VERSION 5.7 ;
BUSBITCHARS "[]" ;
DIVIDERCHAR "/" ;

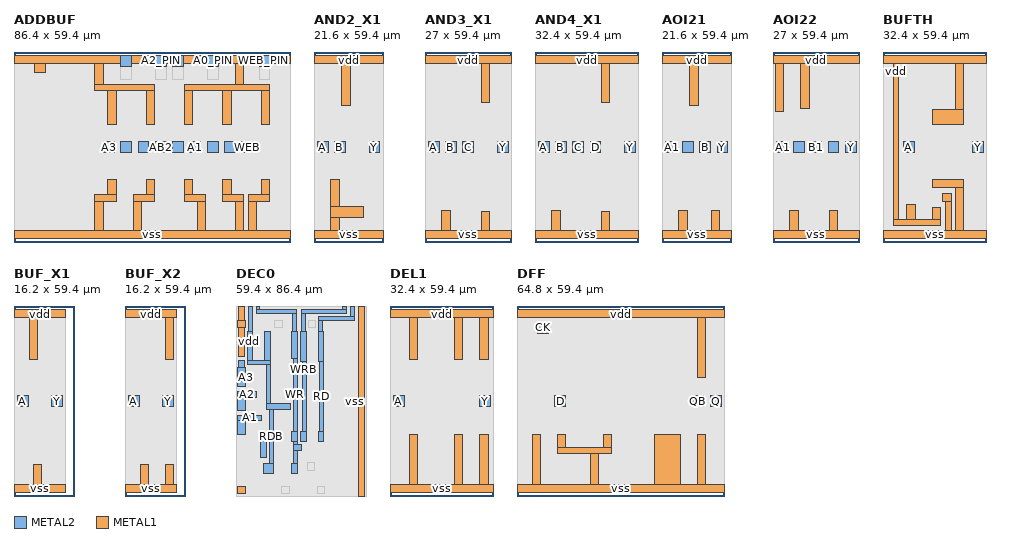
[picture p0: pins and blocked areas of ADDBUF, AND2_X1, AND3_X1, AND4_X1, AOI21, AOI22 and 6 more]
MACRO ADDBUF
  CLASS BLOCK ;
  FOREIGN ADDBUF 48.600 -0.000 ;
  ORIGIN 0.000 0.000 ;
  SIZE 86.400 BY 59.400 ;
  SYMMETRY X Y ;
  PIN A0
    DIRECTION INOUT ;
    USE SIGNAL ;
    PORT
      LAYER METAL2 ;
        RECT 65.800 28.000 69.200 31.400 ;
    END
  END A0
  PIN A0_PIN
    DIRECTION INOUT ;
    USE SIGNAL ;
    PORT
      LAYER METAL2 ;
        RECT 60.400 54.900 63.800 58.300 ;
    END
  END A0_PIN
  PIN A1
    DIRECTION INOUT ;
    USE SIGNAL ;
    PORT
      LAYER METAL2 ;
        RECT 55.000 28.000 58.400 31.400 ;
    END
  END A1
  PIN A1_PIN
    DIRECTION INOUT ;
    USE SIGNAL ;
    PORT
      LAYER METAL2 ;
        RECT 49.600 54.900 53.000 58.300 ;
    END
  END A1_PIN
  PIN A2
    DIRECTION INOUT ;
    USE SIGNAL ;
    PORT
      LAYER METAL2 ;
        RECT 38.800 28.000 42.200 31.400 ;
    END
  END A2
  PIN A2_PIN
    DIRECTION INOUT ;
    USE SIGNAL ;
    PORT
      LAYER METAL2 ;
        RECT 44.200 54.900 47.600 58.300 ;
    END
  END A2_PIN
  PIN A3
    DIRECTION INOUT ;
    USE SIGNAL ;
    PORT
      LAYER METAL2 ;
        RECT 28.000 28.000 31.400 31.400 ;
    END
  END A3
  PIN A3_PIN
    DIRECTION INOUT ;
    USE SIGNAL ;
    PORT
      LAYER METAL2 ;
        RECT 33.400 54.900 36.800 58.300 ;
    END
  END A3_PIN
  PIN AB0
    DIRECTION INOUT ;
    USE SIGNAL ;
    PORT
      LAYER METAL2 ;
        RECT 60.400 28.000 63.800 31.400 ;
    END
  END AB0
  PIN AB1
    DIRECTION INOUT ;
    USE SIGNAL ;
    PORT
      LAYER METAL2 ;
        RECT 49.600 28.000 53.000 31.400 ;
    END
  END AB1
  PIN AB2
    DIRECTION INOUT ;
    USE SIGNAL ;
    PORT
      LAYER METAL2 ;
        RECT 44.200 28.000 47.600 31.400 ;
    END
  END AB2
  PIN AB3
    DIRECTION INOUT ;
    USE SIGNAL ;
    PORT
      LAYER METAL2 ;
        RECT 33.400 28.000 36.800 31.400 ;
    END
  END AB3
  PIN WEB
    DIRECTION INOUT ;
    USE SIGNAL ;
    PORT
      LAYER METAL2 ;
        RECT 71.200 28.000 74.600 31.400 ;
    END
  END WEB
  PIN WEB_PIN
    DIRECTION INOUT ;
    USE SIGNAL ;
    PORT
      LAYER METAL2 ;
        RECT 76.600 54.900 80.000 58.300 ;
    END
  END WEB_PIN
  PIN vdd
    DIRECTION INOUT ;
    USE POWER ;
    PORT
      LAYER METAL1 ;
        RECT 29.300 36.600 31.900 47.400 ;
        RECT 41.300 36.600 43.900 47.400 ;
        RECT 53.300 36.600 55.900 47.400 ;
        RECT 65.300 36.600 67.900 47.400 ;
        RECT 77.300 36.600 79.900 47.400 ;
        RECT 25.300 47.400 43.900 49.200 ;
        RECT 53.300 47.400 79.900 49.200 ;
        RECT 25.300 49.200 27.900 55.700 ;
        RECT 69.300 49.200 71.900 55.700 ;
        RECT 6.400 53.100 9.800 55.700 ;
        RECT 0.000 55.700 86.400 58.300 ;
    END
  END vdd
  PIN vss
    DIRECTION INOUT ;
    USE GROUND ;
    PORT
      LAYER METAL1 ;
        RECT 0.000 1.100 86.400 3.700 ;
        RECT 25.300 3.700 27.900 12.800 ;
        RECT 37.300 3.700 39.900 12.800 ;
        RECT 57.300 3.700 59.900 12.800 ;
        RECT 69.300 3.700 71.900 12.800 ;
        RECT 73.300 3.700 75.900 12.800 ;
        RECT 25.300 12.800 31.900 14.800 ;
        RECT 37.300 12.800 43.900 14.800 ;
        RECT 53.300 12.800 59.900 14.800 ;
        RECT 65.300 12.800 71.900 14.800 ;
        RECT 73.300 12.800 79.900 14.800 ;
        RECT 29.300 14.800 31.900 19.600 ;
        RECT 41.300 14.800 43.900 19.600 ;
        RECT 53.300 14.800 55.900 19.600 ;
        RECT 65.300 14.800 67.900 19.600 ;
        RECT 77.300 14.800 79.900 19.600 ;
    END
  END vss
  OBS
    LAYER METAL1 ;
      RECT 0.000 1.100 86.400 58.300 ;
    LAYER METAL2 ;
      RECT 33.400 50.900 36.800 54.900 ;
      RECT 44.200 50.900 47.600 54.900 ;
      RECT 49.600 50.900 53.000 54.900 ;
      RECT 60.400 50.900 63.800 54.900 ;
      RECT 76.600 50.900 80.000 54.900 ;
  END
END ADDBUF

MACRO AND2_X1
  CLASS CORE ;
  FOREIGN AND2_X1 -0.000 -0.000 ;
  ORIGIN 0.000 0.000 ;
  SIZE 21.600 BY 59.400 ;
  SITE TR1UM ;
  SYMMETRY X Y ;
  PIN A
    DIRECTION INPUT ;
    USE SIGNAL ;
    PORT
      LAYER METAL2 ;
        RECT 1.000 28.000 4.400 31.400 ;
    END
  END A
  PIN B
    DIRECTION INPUT ;
    USE SIGNAL ;
    PORT
      LAYER METAL2 ;
        RECT 6.400 28.000 9.800 31.400 ;
    END
  END B
  PIN Y
    DIRECTION OUTPUT ;
    USE SIGNAL ;
    PORT
      LAYER METAL2 ;
        RECT 17.200 28.000 20.600 31.400 ;
    END
  END Y
  PIN vdd
    DIRECTION INOUT ;
    USE POWER ;
    PORT
      LAYER METAL1 ;
        RECT 8.700 42.700 11.300 55.700 ;
        RECT 0.000 55.700 21.600 58.300 ;
    END
  END vdd
  PIN vss
    DIRECTION INOUT ;
    USE GROUND ;
    PORT
      LAYER METAL1 ;
        RECT 0.000 1.100 21.600 3.700 ;
        RECT 5.300 3.700 7.900 7.700 ;
        RECT 5.300 7.700 15.500 11.100 ;
        RECT 5.300 11.100 7.900 19.600 ;
    END
  END vss
  OBS
    LAYER METAL1 ;
      RECT 0.000 1.100 21.600 58.300 ;
  END
END AND2_X1

MACRO AND3_X1
  CLASS CORE ;
  FOREIGN AND3_X1 -0.000 -0.000 ;
  ORIGIN 0.000 0.000 ;
  SIZE 27.000 BY 59.400 ;
  SITE TR1UM ;
  SYMMETRY X Y ;
  PIN A
    DIRECTION INPUT ;
    USE SIGNAL ;
    PORT
      LAYER METAL2 ;
        RECT 1.000 28.000 4.400 31.400 ;
    END
  END A
  PIN B
    DIRECTION INPUT ;
    USE SIGNAL ;
    PORT
      LAYER METAL2 ;
        RECT 6.400 28.000 9.800 31.400 ;
    END
  END B
  PIN C
    DIRECTION INPUT ;
    USE SIGNAL ;
    PORT
      LAYER METAL2 ;
        RECT 11.800 28.000 15.200 31.400 ;
    END
  END C
  PIN Y
    DIRECTION OUTPUT ;
    USE SIGNAL ;
    PORT
      LAYER METAL2 ;
        RECT 22.600 28.000 26.000 31.400 ;
    END
  END Y
  PIN vdd
    DIRECTION INOUT ;
    USE POWER ;
    PORT
      LAYER METAL1 ;
        RECT 17.700 43.500 20.300 55.700 ;
        RECT 0.000 55.700 27.000 58.300 ;
    END
  END vdd
  PIN vss
    DIRECTION INOUT ;
    USE GROUND ;
    PORT
      LAYER METAL1 ;
        RECT 0.000 1.100 27.000 3.700 ;
        RECT 17.700 3.700 20.300 9.500 ;
        RECT 5.300 3.700 7.900 9.900 ;
    END
  END vss
  OBS
    LAYER METAL1 ;
      RECT 0.000 1.100 27.000 58.300 ;
  END
END AND3_X1

MACRO AND4_X1
  CLASS CORE ;
  FOREIGN AND4_X1 -0.000 -0.000 ;
  ORIGIN 0.000 0.000 ;
  SIZE 32.400 BY 59.400 ;
  SITE TR1UM ;
  SYMMETRY X Y ;
  PIN A
    DIRECTION INPUT ;
    USE SIGNAL ;
    PORT
      LAYER METAL2 ;
        RECT 1.000 28.000 4.400 31.400 ;
    END
  END A
  PIN B
    DIRECTION INPUT ;
    USE SIGNAL ;
    PORT
      LAYER METAL2 ;
        RECT 6.400 28.000 9.800 31.400 ;
    END
  END B
  PIN C
    DIRECTION INPUT ;
    USE SIGNAL ;
    PORT
      LAYER METAL2 ;
        RECT 11.800 28.000 15.200 31.400 ;
    END
  END C
  PIN D
    DIRECTION INPUT ;
    USE SIGNAL ;
    PORT
      LAYER METAL2 ;
        RECT 17.200 28.000 20.600 31.400 ;
    END
  END D
  PIN Y
    DIRECTION OUTPUT ;
    USE SIGNAL ;
    PORT
      LAYER METAL2 ;
        RECT 28.000 28.000 31.400 31.400 ;
    END
  END Y
  PIN vdd
    DIRECTION INOUT ;
    USE POWER ;
    PORT
      LAYER METAL1 ;
        RECT 20.800 43.500 23.400 55.700 ;
        RECT 0.000 55.700 32.400 58.300 ;
    END
  END vdd
  PIN vss
    DIRECTION INOUT ;
    USE GROUND ;
    PORT
      LAYER METAL1 ;
        RECT 0.000 1.100 32.400 3.700 ;
        RECT 20.800 3.700 23.400 9.500 ;
        RECT 5.300 3.700 7.900 9.900 ;
    END
  END vss
  OBS
    LAYER METAL1 ;
      RECT 0.000 1.100 32.400 58.300 ;
  END
END AND4_X1

MACRO AOI21
  CLASS CORE ;
  FOREIGN AOI21 -0.000 -0.000 ;
  ORIGIN 0.000 0.000 ;
  SIZE 21.600 BY 59.400 ;
  SITE TR1UM ;
  SYMMETRY X Y ;
  PIN A1
    DIRECTION INPUT ;
    USE SIGNAL ;
    PORT
      LAYER METAL2 ;
        RECT 1.000 28.000 4.400 31.400 ;
    END
  END A1
  PIN A2
    DIRECTION INPUT ;
    USE SIGNAL ;
    PORT
      LAYER METAL2 ;
        RECT 6.400 28.000 9.800 31.400 ;
    END
  END A2
  PIN B
    DIRECTION INPUT ;
    USE SIGNAL ;
    PORT
      LAYER METAL2 ;
        RECT 11.800 28.000 15.200 31.400 ;
    END
  END B
  PIN Y
    DIRECTION OUTPUT ;
    USE SIGNAL ;
    PORT
      LAYER METAL2 ;
        RECT 17.200 28.000 20.600 31.400 ;
    END
  END Y
  PIN vdd
    DIRECTION INOUT ;
    USE POWER ;
    PORT
      LAYER METAL1 ;
        RECT 8.700 42.700 11.300 55.700 ;
        RECT 0.000 55.700 21.600 58.300 ;
    END
  END vdd
  PIN vss
    DIRECTION INOUT ;
    USE GROUND ;
    PORT
      LAYER METAL1 ;
        RECT 0.000 1.100 21.600 3.700 ;
        RECT 5.300 3.700 7.900 9.900 ;
        RECT 15.500 3.700 18.100 9.900 ;
    END
  END vss
  OBS
    LAYER METAL1 ;
      RECT 0.000 1.100 21.600 58.300 ;
  END
END AOI21

MACRO AOI22
  CLASS CORE ;
  FOREIGN AOI22 -0.000 -0.000 ;
  ORIGIN 0.000 0.000 ;
  SIZE 27.000 BY 59.400 ;
  SITE TR1UM ;
  SYMMETRY X Y ;
  PIN A1
    DIRECTION INPUT ;
    USE SIGNAL ;
    PORT
      LAYER METAL2 ;
        RECT 1.000 28.000 4.400 31.400 ;
    END
  END A1
  PIN A2
    DIRECTION INPUT ;
    USE SIGNAL ;
    PORT
      LAYER METAL2 ;
        RECT 6.400 28.000 9.800 31.400 ;
    END
  END A2
  PIN B1
    DIRECTION INPUT ;
    USE SIGNAL ;
    PORT
      LAYER METAL2 ;
        RECT 11.800 28.000 15.200 31.400 ;
    END
  END B1
  PIN B2
    DIRECTION INPUT ;
    USE SIGNAL ;
    PORT
      LAYER METAL2 ;
        RECT 17.200 28.000 20.600 31.400 ;
    END
  END B2
  PIN Y
    DIRECTION OUTPUT ;
    USE SIGNAL ;
    PORT
      LAYER METAL2 ;
        RECT 22.600 28.000 26.000 31.400 ;
    END
  END Y
  PIN vdd
    DIRECTION INOUT ;
    USE POWER ;
    PORT
      LAYER METAL1 ;
        RECT 0.700 40.900 3.300 55.700 ;
        RECT 8.700 41.700 11.300 55.700 ;
        RECT 0.000 55.700 27.000 58.300 ;
    END
  END vdd
  PIN vss
    DIRECTION INOUT ;
    USE GROUND ;
    PORT
      LAYER METAL1 ;
        RECT 0.000 1.100 27.000 3.700 ;
        RECT 5.300 3.700 7.900 9.900 ;
        RECT 17.700 3.700 20.300 9.900 ;
    END
  END vss
  OBS
    LAYER METAL1 ;
      RECT 0.000 1.100 27.000 58.300 ;
  END
END AOI22

MACRO BUFTH
  CLASS CORE ;
  FOREIGN BUFTH -0.000 -0.000 ;
  ORIGIN 0.000 0.000 ;
  SIZE 32.400 BY 59.400 ;
  SITE TR1UM ;
  SYMMETRY X Y ;
  PIN A
    DIRECTION INPUT ;
    USE SIGNAL ;
    PORT
      LAYER METAL2 ;
        RECT 6.400 28.000 9.800 31.400 ;
    END
  END A
  PIN Y
    DIRECTION OUTPUT ;
    USE SIGNAL ;
    PORT
      LAYER METAL2 ;
        RECT 28.000 28.000 31.400 31.400 ;
    END
  END Y
  PIN vdd
    DIRECTION INOUT ;
    USE POWER ;
    PORT
      LAYER METAL1 ;
        RECT 3.200 5.100 18.100 6.900 ;
        RECT 15.500 6.900 18.100 10.900 ;
        RECT 7.500 6.900 10.100 11.700 ;
        RECT 15.500 36.600 25.300 41.300 ;
        RECT 3.200 6.900 5.000 55.700 ;
        RECT 22.700 41.300 25.300 55.700 ;
        RECT 0.000 55.700 32.400 58.300 ;
    END
  END vdd
  PIN vss
    DIRECTION INOUT ;
    USE GROUND ;
    PORT
      LAYER METAL1 ;
        RECT 0.000 1.100 32.400 3.700 ;
        RECT 19.500 3.700 21.300 12.700 ;
        RECT 18.700 12.700 21.300 15.300 ;
        RECT 22.700 3.700 25.300 17.000 ;
        RECT 15.500 17.000 25.300 19.600 ;
    END
  END vss
  OBS
    LAYER METAL1 ;
      RECT 0.000 1.100 32.400 58.300 ;
  END
END BUFTH

MACRO BUF_X1
  CLASS CORE ;
  FOREIGN BUF_X1 -0.000 -0.000 ;
  ORIGIN 0.000 0.000 ;
  SIZE 16.200 BY 59.400 ;
  SITE TR1UM ;
  SYMMETRY X Y ;
  PIN A
    DIRECTION INPUT ;
    USE SIGNAL ;
    PORT
      LAYER METAL2 ;
        RECT 1.000 28.000 4.400 31.400 ;
    END
  END A
  PIN Y
    DIRECTION OUTPUT ;
    USE SIGNAL ;
    PORT
      LAYER METAL2 ;
        RECT 11.800 28.000 15.200 31.400 ;
    END
  END Y
  PIN vdd
    DIRECTION INOUT ;
    USE POWER ;
    PORT
      LAYER METAL1 ;
        RECT 4.700 42.700 7.300 55.700 ;
        RECT 0.000 55.700 16.200 58.300 ;
    END
  END vdd
  PIN vss
    DIRECTION INOUT ;
    USE GROUND ;
    PORT
      LAYER METAL1 ;
        RECT 0.000 1.100 16.200 3.700 ;
        RECT 6.100 3.700 8.700 9.900 ;
    END
  END vss
  OBS
    LAYER METAL1 ;
      RECT 0.000 1.100 16.200 58.300 ;
  END
END BUF_X1

MACRO BUF_X2
  CLASS CORE ;
  FOREIGN BUF_X2 -0.000 -0.000 ;
  ORIGIN 0.000 0.000 ;
  SIZE 16.200 BY 59.400 ;
  SITE TR1UM ;
  SYMMETRY X Y ;
  PIN A
    DIRECTION INPUT ;
    USE SIGNAL ;
    PORT
      LAYER METAL2 ;
        RECT 1.000 28.000 4.400 31.400 ;
    END
  END A
  PIN Y
    DIRECTION OUTPUT ;
    USE SIGNAL ;
    PORT
      LAYER METAL2 ;
        RECT 11.800 28.000 15.200 31.400 ;
    END
  END Y
  PIN vdd
    DIRECTION INOUT ;
    USE POWER ;
    PORT
      LAYER METAL1 ;
        RECT 12.700 42.700 15.300 55.700 ;
        RECT 0.000 55.700 16.200 58.300 ;
    END
  END vdd
  PIN vss
    DIRECTION INOUT ;
    USE GROUND ;
    PORT
      LAYER METAL1 ;
        RECT 0.000 1.100 16.200 3.700 ;
        RECT 4.700 3.700 7.300 9.900 ;
        RECT 12.700 3.700 15.300 9.900 ;
    END
  END vss
  OBS
    LAYER METAL1 ;
      RECT 0.000 1.100 16.200 58.300 ;
  END
END BUF_X2

MACRO DEC0
  CLASS BLOCK ;
  FOREIGN DEC0 2.400 -0.000 ;
  ORIGIN 0.000 0.000 ;
  SIZE 59.400 BY 86.400 ;
  SYMMETRY X Y ;
  PIN A1
    DIRECTION INOUT ;
    USE SIGNAL ;
    PORT
      LAYER METAL2 ;
        RECT 11.200 17.600 13.800 25.600 ;
        RECT 0.700 28.000 4.100 34.200 ;
        RECT 0.700 34.200 11.600 36.800 ;
    END
  END A1
  PIN A2
    DIRECTION INOUT ;
    USE SIGNAL ;
    PORT
      LAYER METAL2 ;
        RECT 0.700 38.800 4.100 45.000 ;
        RECT 0.700 45.000 9.400 47.600 ;
    END
  END A2
  PIN A3
    DIRECTION INOUT ;
    USE SIGNAL ;
    PORT
      LAYER METAL2 ;
        RECT 0.700 49.600 4.100 58.400 ;
        RECT 1.100 58.400 3.700 61.400 ;
    END
  END A3
  PIN RD
    DIRECTION INOUT ;
    USE SIGNAL ;
    PORT
      LAYER METAL2 ;
        RECT 37.300 24.600 39.900 29.200 ;
        RECT 38.100 29.200 39.900 61.000 ;
        RECT 37.300 61.000 39.900 74.900 ;
        RECT 37.700 74.900 39.500 79.700 ;
        RECT 37.700 79.700 53.900 81.500 ;
        RECT 52.100 81.500 53.900 86.400 ;
    END
  END RD
  PIN RDB
    DIRECTION INOUT ;
    USE SIGNAL ;
    PORT
      LAYER METAL2 ;
        RECT 12.700 10.100 17.000 14.700 ;
        RECT 15.200 14.700 17.000 39.400 ;
        RECT 13.900 39.400 24.700 42.000 ;
        RECT 13.900 42.000 15.700 59.800 ;
        RECT 5.100 59.800 15.700 61.600 ;
        RECT 5.100 61.600 7.700 74.900 ;
        RECT 13.100 61.600 15.700 74.900 ;
        RECT 5.500 74.900 7.300 86.400 ;
    END
  END RDB
  PIN WR
    DIRECTION INOUT ;
    USE SIGNAL ;
    PORT
      LAYER METAL2 ;
        RECT 25.300 10.100 27.900 14.700 ;
        RECT 26.100 14.700 27.900 20.600 ;
        RECT 26.100 20.600 29.700 23.200 ;
        RECT 26.100 23.200 27.900 24.600 ;
        RECT 25.300 24.600 27.900 29.200 ;
        RECT 26.100 29.200 27.900 62.700 ;
        RECT 25.300 62.700 27.900 74.900 ;
        RECT 25.700 74.900 27.500 82.900 ;
        RECT 9.100 82.900 27.500 84.700 ;
        RECT 9.100 84.700 10.900 86.400 ;
    END
  END WR
  PIN WRB
    DIRECTION INOUT ;
    USE SIGNAL ;
    PORT
      LAYER METAL2 ;
        RECT 29.300 24.600 31.900 29.200 ;
        RECT 30.100 29.200 31.900 61.000 ;
        RECT 29.300 61.000 31.900 74.900 ;
        RECT 29.700 74.900 31.500 82.900 ;
        RECT 29.700 82.900 50.300 84.700 ;
        RECT 48.500 84.700 50.300 86.400 ;
    END
  END WRB
  PIN vdd
    DIRECTION INOUT ;
    USE POWER ;
    PORT
      LAYER METAL1 ;
        RECT 0.700 76.600 4.100 80.000 ;
        RECT 1.100 63.500 3.700 76.600 ;
        RECT 0.700 76.600 4.100 80.000 ;
        RECT 1.100 80.000 3.700 86.400 ;
    END
  END vdd
  PIN vss
    DIRECTION INOUT ;
    USE GROUND ;
    PORT
      LAYER METAL1 ;
        RECT 0.700 1.000 4.100 4.400 ;
        RECT 55.700 0.000 58.300 86.400 ;
    END
  END vss
  OBS
    LAYER METAL1 ;
      RECT 0.000 0.000 59.400 86.400 ;
    LAYER METAL2 ;
      RECT 20.900 1.000 24.300 4.400 ;
      RECT 36.900 1.000 40.300 4.400 ;
      RECT 32.500 11.800 35.900 15.200 ;
      RECT 17.700 76.600 21.100 80.000 ;
      RECT 32.900 76.600 36.300 80.000 ;
  END
END DEC0

MACRO DEC16
  CLASS BLOCK ;
  FOREIGN DEC16 57.000 0.000 ;
  ORIGIN 0.000 0.000 ;
  SIZE 878.400 BY 86.400 ;
  SYMMETRY X Y ;
  # ★ ピン未定義: GDS のトップにラベル/(49,1) 形状を入れて再生成すること

  OBS
    LAYER METAL1 ;
      RECT 0.000 0.000 878.400 86.400 ;
    LAYER METAL2 ;
      RECT 0.000 0.000 878.400 86.400 ;
  END
END DEC16

MACRO DEC2
  CLASS BLOCK ;
  FOREIGN DEC2 57.000 0.000 ;
  ORIGIN 0.000 0.000 ;
  SIZE 114.000 BY 86.400 ;
  SYMMETRY X Y ;
  # ★ ピン未定義: GDS のトップにラベル/(49,1) 形状を入れて再生成すること

  OBS
    LAYER METAL1 ;
      RECT 0.000 0.000 114.000 86.400 ;
    LAYER METAL2 ;
      RECT 0.000 0.000 114.000 86.400 ;
  END
END DEC2

MACRO DEL1
  CLASS CORE ;
  FOREIGN DEL1 -0.000 -0.000 ;
  ORIGIN 0.000 0.000 ;
  SIZE 32.400 BY 59.400 ;
  SITE TR1UM ;
  SYMMETRY X Y ;
  PIN A
    DIRECTION INPUT ;
    USE SIGNAL ;
    PORT
      LAYER METAL2 ;
        RECT 1.000 28.000 4.400 31.400 ;
    END
  END A
  PIN Y
    DIRECTION OUTPUT ;
    USE SIGNAL ;
    PORT
      LAYER METAL2 ;
        RECT 28.000 28.000 31.400 31.400 ;
    END
  END Y
  PIN vdd
    DIRECTION INOUT ;
    USE POWER ;
    PORT
      LAYER METAL1 ;
        RECT 6.100 42.700 8.700 55.700 ;
        RECT 20.100 42.700 22.700 55.700 ;
        RECT 28.100 42.700 30.700 55.700 ;
        RECT 0.000 55.700 32.400 58.300 ;
    END
  END vdd
  PIN vss
    DIRECTION INOUT ;
    USE GROUND ;
    PORT
      LAYER METAL1 ;
        RECT 0.000 1.100 32.400 3.700 ;
        RECT 6.100 3.700 8.700 19.100 ;
        RECT 20.100 3.700 22.700 19.100 ;
        RECT 28.100 3.700 30.700 19.100 ;
    END
  END vss
  OBS
    LAYER METAL1 ;
      RECT 0.000 1.100 32.400 58.300 ;
  END
END DEL1

MACRO DFF
  CLASS CORE ;
  FOREIGN DFF -0.000 -0.000 ;
  ORIGIN 0.000 0.000 ;
  SIZE 64.800 BY 59.400 ;
  SITE TR1UM ;
  SYMMETRY X Y ;
  PIN CK
    DIRECTION INPUT ;
    USE SIGNAL ;
    PORT
      LAYER METAL2 ;
        RECT 6.400 50.900 9.800 54.300 ;
    END
  END CK
  PIN D
    DIRECTION INPUT ;
    USE SIGNAL ;
    PORT
      LAYER METAL2 ;
        RECT 11.800 27.900 15.200 31.300 ;
    END
  END D
  PIN Q
    DIRECTION OUTPUT ;
    USE SIGNAL ;
    PORT
      LAYER METAL2 ;
        RECT 60.400 27.900 63.800 31.300 ;
    END
  END Q
  PIN QB
    DIRECTION OUTPUT ;
    USE SIGNAL ;
    PORT
      LAYER METAL2 ;
        RECT 55.000 27.900 58.400 31.300 ;
    END
  END QB
  PIN vdd
    DIRECTION INOUT ;
    USE POWER ;
    PORT
      LAYER METAL1 ;
        RECT 56.400 36.900 59.000 55.700 ;
        RECT 0.000 55.700 64.800 58.300 ;
    END
  END vdd
  PIN vss
    DIRECTION INOUT ;
    USE GROUND ;
    PORT
      LAYER METAL1 ;
        RECT 0.000 1.100 64.800 3.700 ;
        RECT 22.900 3.700 25.500 13.400 ;
        RECT 12.700 13.400 29.500 15.200 ;
        RECT 4.700 3.700 7.300 19.200 ;
        RECT 42.900 3.700 51.000 19.200 ;
        RECT 56.400 3.700 59.000 19.200 ;
        RECT 12.700 15.200 15.300 19.200 ;
        RECT 26.900 15.200 29.500 19.200 ;
    END
  END vss
  OBS
    LAYER METAL1 ;
      RECT 0.000 1.100 64.800 58.300 ;
  END
END DFF

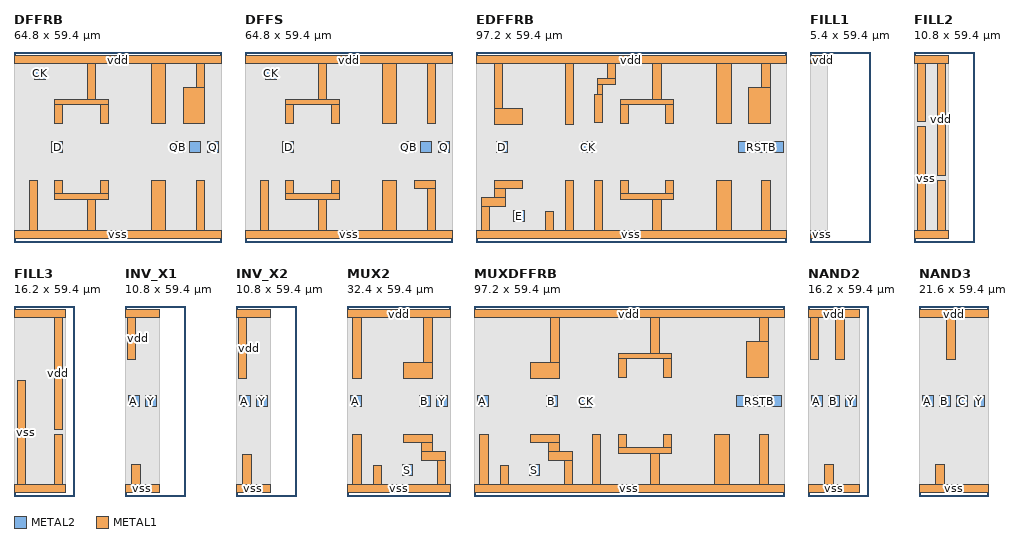
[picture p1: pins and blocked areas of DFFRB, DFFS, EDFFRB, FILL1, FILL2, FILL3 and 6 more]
MACRO DFFRB
  CLASS CORE ;
  FOREIGN DFFRB -0.000 -0.000 ;
  ORIGIN 0.000 0.000 ;
  SIZE 64.800 BY 59.400 ;
  SITE TR1UM ;
  SYMMETRY X Y ;
  PIN CK
    DIRECTION INPUT ;
    USE SIGNAL ;
    PORT
      LAYER METAL2 ;
        RECT 6.400 50.900 9.800 54.300 ;
    END
  END CK
  PIN D
    DIRECTION INPUT ;
    USE SIGNAL ;
    PORT
      LAYER METAL2 ;
        RECT 11.800 27.900 15.200 31.300 ;
    END
  END D
  PIN Q
    DIRECTION OUTPUT ;
    USE SIGNAL ;
    PORT
      LAYER METAL2 ;
        RECT 60.400 27.900 63.800 31.300 ;
    END
  END Q
  PIN QB
    DIRECTION OUTPUT ;
    USE SIGNAL ;
    PORT
      LAYER METAL2 ;
        RECT 49.600 27.900 53.000 31.300 ;
    END
  END QB
  PIN RSTB
    DIRECTION INPUT ;
    USE SIGNAL ;
    PORT
      LAYER METAL2 ;
        RECT 55.000 27.900 58.400 31.300 ;
    END
  END RSTB
  PIN vdd
    DIRECTION INOUT ;
    USE POWER ;
    PORT
      LAYER METAL1 ;
        RECT 12.700 36.900 15.300 42.900 ;
        RECT 26.900 36.900 29.500 42.900 ;
        RECT 12.700 42.900 29.500 44.700 ;
        RECT 52.900 36.900 59.600 48.400 ;
        RECT 42.900 36.900 47.500 55.700 ;
        RECT 22.900 44.700 25.500 55.700 ;
        RECT 57.000 48.400 59.600 55.700 ;
        RECT 0.000 55.700 64.800 58.300 ;
    END
  END vdd
  PIN vss
    DIRECTION INOUT ;
    USE GROUND ;
    PORT
      LAYER METAL1 ;
        RECT 0.000 1.100 64.800 3.700 ;
        RECT 22.900 3.700 25.500 13.400 ;
        RECT 12.700 13.400 29.500 15.200 ;
        RECT 4.700 3.700 7.300 19.200 ;
        RECT 42.900 3.700 47.500 19.200 ;
        RECT 57.000 3.700 59.600 19.200 ;
        RECT 12.700 15.200 15.300 19.200 ;
        RECT 26.900 15.200 29.500 19.200 ;
    END
  END vss
  OBS
    LAYER METAL1 ;
      RECT 0.000 1.100 64.800 58.300 ;
  END
END DFFRB

MACRO DFFS
  CLASS CORE ;
  FOREIGN DFFS -0.000 -0.000 ;
  ORIGIN 0.000 0.000 ;
  SIZE 64.800 BY 59.400 ;
  SITE TR1UM ;
  SYMMETRY X Y ;
  PIN CK
    DIRECTION INPUT ;
    USE SIGNAL ;
    PORT
      LAYER METAL2 ;
        RECT 6.400 50.900 9.800 54.300 ;
    END
  END CK
  PIN D
    DIRECTION INPUT ;
    USE SIGNAL ;
    PORT
      LAYER METAL2 ;
        RECT 11.800 27.900 15.200 31.300 ;
    END
  END D
  PIN Q
    DIRECTION OUTPUT ;
    USE SIGNAL ;
    PORT
      LAYER METAL2 ;
        RECT 60.400 27.900 63.800 31.300 ;
    END
  END Q
  PIN QB
    DIRECTION OUTPUT ;
    USE SIGNAL ;
    PORT
      LAYER METAL2 ;
        RECT 49.600 27.900 53.000 31.300 ;
    END
  END QB
  PIN SET
    DIRECTION INPUT ;
    USE SIGNAL ;
    PORT
      LAYER METAL2 ;
        RECT 55.000 27.900 58.400 31.300 ;
    END
  END SET
  PIN vdd
    DIRECTION INOUT ;
    USE POWER ;
    PORT
      LAYER METAL1 ;
        RECT 12.700 36.900 15.300 42.900 ;
        RECT 26.900 36.900 29.500 42.900 ;
        RECT 12.700 42.900 29.500 44.700 ;
        RECT 42.900 36.900 47.500 55.700 ;
        RECT 57.000 36.900 59.600 55.700 ;
        RECT 22.900 44.700 25.500 55.700 ;
        RECT 0.000 55.700 64.800 58.300 ;
    END
  END vdd
  PIN vss
    DIRECTION INOUT ;
    USE GROUND ;
    PORT
      LAYER METAL1 ;
        RECT 0.000 1.100 64.800 3.700 ;
        RECT 22.900 3.700 25.500 13.400 ;
        RECT 12.700 13.400 29.500 15.200 ;
        RECT 57.000 3.700 59.600 16.600 ;
        RECT 4.700 3.700 7.300 19.200 ;
        RECT 42.900 3.700 47.500 19.200 ;
        RECT 12.700 15.200 15.300 19.200 ;
        RECT 26.900 15.200 29.500 19.200 ;
        RECT 52.900 16.600 59.600 19.200 ;
    END
  END vss
  OBS
    LAYER METAL1 ;
      RECT 0.000 1.100 64.800 58.300 ;
  END
END DFFS

MACRO EDFFRB
  CLASS CORE ;
  FOREIGN EDFFRB -0.000 -0.000 ;
  ORIGIN 0.000 0.000 ;
  SIZE 97.200 BY 59.400 ;
  SITE TR1UM ;
  SYMMETRY X Y ;
  PIN CK
    DIRECTION INPUT ;
    USE SIGNAL ;
    PORT
      LAYER METAL2 ;
        RECT 33.400 27.900 36.800 31.300 ;
    END
  END CK
  PIN D
    DIRECTION INPUT ;
    USE SIGNAL ;
    PORT
      LAYER METAL2 ;
        RECT 6.400 27.900 9.800 31.300 ;
    END
  END D
  PIN E
    DIRECTION INPUT ;
    USE SIGNAL ;
    PORT
      LAYER METAL2 ;
        RECT 11.800 6.300 15.200 9.700 ;
    END
  END E
  PIN Q
    DIRECTION OUTPUT ;
    USE SIGNAL ;
    PORT
      LAYER METAL2 ;
        RECT 92.800 27.900 96.200 31.300 ;
    END
  END Q
  PIN QB
    DIRECTION OUTPUT ;
    USE SIGNAL ;
    PORT
      LAYER METAL2 ;
        RECT 82.000 27.900 85.400 31.300 ;
    END
  END QB
  PIN RSTB
    DIRECTION INPUT ;
    USE SIGNAL ;
    PORT
      LAYER METAL2 ;
        RECT 87.400 27.900 90.800 31.300 ;
    END
  END RSTB
  PIN vdd
    DIRECTION INOUT ;
    USE POWER ;
    PORT
      LAYER METAL1 ;
        RECT 5.800 36.700 14.600 41.700 ;
        RECT 45.100 36.900 47.700 42.900 ;
        RECT 59.300 36.900 61.900 42.900 ;
        RECT 45.100 42.900 61.900 44.700 ;
        RECT 37.100 37.500 39.700 46.100 ;
        RECT 85.300 36.900 92.000 48.400 ;
        RECT 37.900 46.100 39.700 49.300 ;
        RECT 37.900 49.300 43.700 51.100 ;
        RECT 28.000 36.700 30.600 55.700 ;
        RECT 75.300 36.900 79.900 55.700 ;
        RECT 5.800 41.700 8.400 55.700 ;
        RECT 55.300 44.700 57.900 55.700 ;
        RECT 89.400 48.400 92.000 55.700 ;
        RECT 41.100 51.100 43.700 55.700 ;
        RECT 0.000 55.700 97.200 58.300 ;
    END
  END vdd
  PIN vss
    DIRECTION INOUT ;
    USE GROUND ;
    PORT
      LAYER METAL1 ;
        RECT 0.000 1.100 97.200 3.700 ;
        RECT 21.600 3.700 24.200 9.500 ;
        RECT 1.600 3.700 4.200 11.200 ;
        RECT 55.300 3.700 57.900 13.400 ;
        RECT 1.600 11.200 9.100 13.800 ;
        RECT 45.100 13.400 61.900 15.200 ;
        RECT 5.800 13.800 9.100 16.600 ;
        RECT 37.100 3.700 39.700 19.200 ;
        RECT 75.300 3.700 79.900 19.200 ;
        RECT 89.400 3.700 92.000 19.200 ;
        RECT 45.100 15.200 47.700 19.200 ;
        RECT 59.300 15.200 61.900 19.200 ;
        RECT 28.000 3.700 30.600 19.300 ;
        RECT 5.800 16.600 14.600 19.300 ;
    END
  END vss
  OBS
    LAYER METAL1 ;
      RECT 0.000 1.100 97.200 58.300 ;
  END
END EDFFRB

MACRO FILL1
  CLASS CORE SPACER ;
  FOREIGN FILL1 -0.000 -0.000 ;
  ORIGIN 0.000 0.000 ;
  SIZE 5.400 BY 59.400 ;
  SITE TR1UM ;
  SYMMETRY X Y ;
  PIN vdd
    DIRECTION INOUT ;
    USE POWER ;
    PORT
      LAYER METAL1 ;
        RECT 0.000 55.700 5.400 58.300 ;
    END
  END vdd
  PIN vss
    DIRECTION INOUT ;
    USE GROUND ;
    PORT
      LAYER METAL1 ;
        RECT 0.000 1.100 5.400 3.700 ;
    END
  END vss
  OBS
    LAYER METAL1 ;
      RECT 0.000 1.100 5.400 58.300 ;
  END
END FILL1

MACRO FILL2
  CLASS CORE SPACER ;
  FOREIGN FILL2 -0.000 -0.000 ;
  ORIGIN 0.000 0.000 ;
  SIZE 10.800 BY 59.400 ;
  SITE TR1UM ;
  SYMMETRY X Y ;
  PIN vdd
    DIRECTION INOUT ;
    USE POWER ;
    PORT
      LAYER METAL1 ;
        RECT 7.200 20.700 9.800 55.700 ;
        RECT 1.000 37.700 3.600 55.700 ;
        RECT 0.000 55.700 10.800 58.300 ;
    END
  END vdd
  PIN vss
    DIRECTION INOUT ;
    USE GROUND ;
    PORT
      LAYER METAL1 ;
        RECT 0.000 1.100 10.800 3.700 ;
        RECT 7.200 3.700 9.800 19.100 ;
        RECT 1.000 3.700 3.600 36.100 ;
    END
  END vss
  OBS
    LAYER METAL1 ;
      RECT 0.000 1.100 10.800 58.300 ;
  END
END FILL2

MACRO FILL3
  CLASS CORE SPACER ;
  FOREIGN FILL3 -0.000 -0.000 ;
  ORIGIN 0.000 0.000 ;
  SIZE 16.200 BY 59.400 ;
  SITE TR1UM ;
  SYMMETRY X Y ;
  PIN vdd
    DIRECTION INOUT ;
    USE POWER ;
    PORT
      LAYER METAL1 ;
        RECT 12.600 20.700 15.200 55.700 ;
        RECT 0.000 55.700 16.200 58.300 ;
    END
  END vdd
  PIN vss
    DIRECTION INOUT ;
    USE GROUND ;
    PORT
      LAYER METAL1 ;
        RECT 0.000 1.100 16.200 3.700 ;
        RECT 12.600 3.700 15.200 19.100 ;
        RECT 1.000 3.700 3.600 36.100 ;
    END
  END vss
  OBS
    LAYER METAL1 ;
      RECT 0.000 1.100 16.200 58.300 ;
  END
END FILL3

MACRO INV_X1
  CLASS CORE ;
  FOREIGN INV_X1 -0.000 -0.000 ;
  ORIGIN 0.000 0.000 ;
  SIZE 10.800 BY 59.400 ;
  SITE TR1UM ;
  SYMMETRY X Y ;
  PIN A
    DIRECTION INPUT ;
    USE SIGNAL ;
    PORT
      LAYER METAL2 ;
        RECT 1.000 28.000 4.400 31.400 ;
    END
  END A
  PIN Y
    DIRECTION OUTPUT ;
    USE SIGNAL ;
    PORT
      LAYER METAL2 ;
        RECT 6.400 28.000 9.800 31.400 ;
    END
  END Y
  PIN vdd
    DIRECTION INOUT ;
    USE POWER ;
    PORT
      LAYER METAL1 ;
        RECT 0.700 42.700 3.300 55.700 ;
        RECT 0.000 55.700 10.800 58.300 ;
    END
  END vdd
  PIN vss
    DIRECTION INOUT ;
    USE GROUND ;
    PORT
      LAYER METAL1 ;
        RECT 0.000 1.100 10.800 3.700 ;
        RECT 2.100 3.700 4.700 9.900 ;
    END
  END vss
  OBS
    LAYER METAL1 ;
      RECT 0.000 1.100 10.800 58.300 ;
  END
END INV_X1

MACRO INV_X2
  CLASS CORE ;
  FOREIGN INV_X2 -0.000 -0.000 ;
  ORIGIN 0.000 0.000 ;
  SIZE 10.800 BY 59.400 ;
  SITE TR1UM ;
  SYMMETRY X Y ;
  PIN A
    DIRECTION INPUT ;
    USE SIGNAL ;
    PORT
      LAYER METAL2 ;
        RECT 1.000 28.000 4.400 31.400 ;
    END
  END A
  PIN Y
    DIRECTION OUTPUT ;
    USE SIGNAL ;
    PORT
      LAYER METAL2 ;
        RECT 6.400 28.000 9.800 31.400 ;
    END
  END Y
  PIN vdd
    DIRECTION INOUT ;
    USE POWER ;
    PORT
      LAYER METAL1 ;
        RECT 0.700 36.700 3.300 55.700 ;
        RECT 0.000 55.700 10.800 58.300 ;
    END
  END vdd
  PIN vss
    DIRECTION INOUT ;
    USE GROUND ;
    PORT
      LAYER METAL1 ;
        RECT 0.000 1.100 10.800 3.700 ;
        RECT 2.100 3.700 4.700 13.100 ;
    END
  END vss
  OBS
    LAYER METAL1 ;
      RECT 0.000 1.100 10.800 58.300 ;
  END
END INV_X2

MACRO MUX2
  CLASS CORE ;
  FOREIGN MUX2 -0.000 -0.000 ;
  ORIGIN 0.000 0.000 ;
  SIZE 32.400 BY 59.400 ;
  SITE TR1UM ;
  SYMMETRY X Y ;
  PIN A
    DIRECTION INPUT ;
    USE SIGNAL ;
    PORT
      LAYER METAL2 ;
        RECT 1.000 27.900 4.400 31.300 ;
    END
  END A
  PIN B
    DIRECTION INPUT ;
    USE SIGNAL ;
    PORT
      LAYER METAL2 ;
        RECT 22.600 27.900 26.000 31.300 ;
    END
  END B
  PIN S
    DIRECTION INPUT ;
    USE SIGNAL ;
    PORT
      LAYER METAL2 ;
        RECT 17.200 6.300 20.600 9.700 ;
    END
  END S
  PIN Y
    DIRECTION OUTPUT ;
    USE SIGNAL ;
    PORT
      LAYER METAL2 ;
        RECT 28.000 27.900 31.400 31.300 ;
    END
  END Y
  PIN vdd
    DIRECTION INOUT ;
    USE POWER ;
    PORT
      LAYER METAL1 ;
        RECT 17.800 36.700 26.600 41.700 ;
        RECT 1.800 36.700 4.400 55.700 ;
        RECT 24.000 41.700 26.600 55.700 ;
        RECT 0.000 55.700 32.400 58.300 ;
    END
  END vdd
  PIN vss
    DIRECTION INOUT ;
    USE GROUND ;
    PORT
      LAYER METAL1 ;
        RECT 0.000 1.100 32.400 3.700 ;
        RECT 8.200 3.700 10.800 9.500 ;
        RECT 28.200 3.700 30.800 11.200 ;
        RECT 23.300 11.200 30.800 13.800 ;
        RECT 23.300 13.800 26.600 16.600 ;
        RECT 1.800 3.700 4.400 19.300 ;
        RECT 17.800 16.600 26.600 19.300 ;
    END
  END vss
  OBS
    LAYER METAL1 ;
      RECT 0.000 1.100 32.400 58.300 ;
  END
END MUX2

MACRO MUXDFFRB
  CLASS CORE ;
  FOREIGN MUXDFFRB -0.000 -0.000 ;
  ORIGIN 0.000 0.000 ;
  SIZE 97.200 BY 59.400 ;
  SITE TR1UM ;
  SYMMETRY X Y ;
  PIN A
    DIRECTION INPUT ;
    USE SIGNAL ;
    PORT
      LAYER METAL2 ;
        RECT 1.000 27.900 4.400 31.300 ;
    END
  END A
  PIN B
    DIRECTION INPUT ;
    USE SIGNAL ;
    PORT
      LAYER METAL2 ;
        RECT 22.600 27.900 26.000 31.300 ;
    END
  END B
  PIN CK
    DIRECTION INPUT ;
    USE SIGNAL ;
    PORT
      LAYER METAL2 ;
        RECT 33.400 27.700 36.800 31.100 ;
    END
  END CK
  PIN Q
    DIRECTION OUTPUT ;
    USE SIGNAL ;
    PORT
      LAYER METAL2 ;
        RECT 92.800 27.900 96.200 31.300 ;
    END
  END Q
  PIN QB
    DIRECTION OUTPUT ;
    USE SIGNAL ;
    PORT
      LAYER METAL2 ;
        RECT 82.000 27.900 85.400 31.300 ;
    END
  END QB
  PIN RSTB
    DIRECTION INPUT ;
    USE SIGNAL ;
    PORT
      LAYER METAL2 ;
        RECT 87.400 27.900 90.800 31.300 ;
    END
  END RSTB
  PIN S
    DIRECTION INPUT ;
    USE SIGNAL ;
    PORT
      LAYER METAL2 ;
        RECT 17.200 6.300 20.600 9.700 ;
    END
  END S
  PIN vdd
    DIRECTION INOUT ;
    USE POWER ;
    PORT
      LAYER METAL1 ;
        RECT 17.800 36.700 26.600 41.700 ;
        RECT 45.100 36.900 47.700 42.900 ;
        RECT 59.300 36.900 61.900 42.900 ;
        RECT 45.100 42.900 61.900 44.700 ;
        RECT 85.300 36.900 92.000 48.400 ;
        RECT 24.000 41.700 26.600 55.700 ;
        RECT 55.300 44.700 57.900 55.700 ;
        RECT 89.400 48.400 92.000 55.700 ;
        RECT 0.000 55.700 97.200 58.300 ;
    END
  END vdd
  PIN vss
    DIRECTION INOUT ;
    USE GROUND ;
    PORT
      LAYER METAL1 ;
        RECT 0.000 1.100 97.200 3.700 ;
        RECT 8.200 3.700 10.800 9.500 ;
        RECT 28.200 3.700 30.800 11.200 ;
        RECT 55.300 3.700 57.900 13.400 ;
        RECT 23.300 11.200 30.800 13.800 ;
        RECT 45.100 13.400 61.900 15.200 ;
        RECT 23.300 13.800 26.600 16.600 ;
        RECT 37.100 3.700 39.700 19.200 ;
        RECT 75.300 3.700 79.900 19.200 ;
        RECT 89.400 3.700 92.000 19.200 ;
        RECT 45.100 15.200 47.700 19.200 ;
        RECT 59.300 15.200 61.900 19.200 ;
        RECT 1.800 3.700 4.400 19.300 ;
        RECT 17.800 16.600 26.600 19.300 ;
    END
  END vss
  OBS
    LAYER METAL1 ;
      RECT 0.000 1.100 97.200 58.300 ;
  END
END MUXDFFRB

MACRO NAND2
  CLASS CORE ;
  FOREIGN NAND2 -0.000 -0.000 ;
  ORIGIN 0.000 0.000 ;
  SIZE 16.200 BY 59.400 ;
  SITE TR1UM ;
  SYMMETRY X Y ;
  PIN A
    DIRECTION INPUT ;
    USE SIGNAL ;
    PORT
      LAYER METAL2 ;
        RECT 1.000 28.000 4.400 31.400 ;
    END
  END A
  PIN B
    DIRECTION INPUT ;
    USE SIGNAL ;
    PORT
      LAYER METAL2 ;
        RECT 6.400 28.000 9.800 31.400 ;
    END
  END B
  PIN Y
    DIRECTION OUTPUT ;
    USE SIGNAL ;
    PORT
      LAYER METAL2 ;
        RECT 11.800 28.000 15.200 31.400 ;
    END
  END Y
  PIN vdd
    DIRECTION INOUT ;
    USE POWER ;
    PORT
      LAYER METAL1 ;
        RECT 0.700 42.700 3.300 55.700 ;
        RECT 8.700 42.700 11.300 55.700 ;
        RECT 0.000 55.700 16.200 58.300 ;
    END
  END vdd
  PIN vss
    DIRECTION INOUT ;
    USE GROUND ;
    PORT
      LAYER METAL1 ;
        RECT 0.000 1.100 16.200 3.700 ;
        RECT 5.300 3.700 7.900 9.900 ;
    END
  END vss
  OBS
    LAYER METAL1 ;
      RECT 0.000 1.100 16.200 58.300 ;
  END
END NAND2

MACRO NAND3
  CLASS CORE ;
  FOREIGN NAND3 -0.000 -0.000 ;
  ORIGIN 0.000 0.000 ;
  SIZE 21.600 BY 59.400 ;
  SITE TR1UM ;
  SYMMETRY X Y ;
  PIN A
    DIRECTION INPUT ;
    USE SIGNAL ;
    PORT
      LAYER METAL2 ;
        RECT 1.000 28.000 4.400 31.400 ;
    END
  END A
  PIN B
    DIRECTION INPUT ;
    USE SIGNAL ;
    PORT
      LAYER METAL2 ;
        RECT 6.400 28.000 9.800 31.400 ;
    END
  END B
  PIN C
    DIRECTION INPUT ;
    USE SIGNAL ;
    PORT
      LAYER METAL2 ;
        RECT 11.800 28.000 15.200 31.400 ;
    END
  END C
  PIN Y
    DIRECTION OUTPUT ;
    USE SIGNAL ;
    PORT
      LAYER METAL2 ;
        RECT 17.200 28.000 20.600 31.400 ;
    END
  END Y
  PIN vdd
    DIRECTION INOUT ;
    USE POWER ;
    PORT
      LAYER METAL1 ;
        RECT 8.700 42.700 11.300 55.700 ;
        RECT 0.000 55.700 21.600 58.300 ;
    END
  END vdd
  PIN vss
    DIRECTION INOUT ;
    USE GROUND ;
    PORT
      LAYER METAL1 ;
        RECT 0.000 1.100 21.600 3.700 ;
        RECT 5.300 3.700 7.900 9.900 ;
    END
  END vss
  OBS
    LAYER METAL1 ;
      RECT 0.000 1.100 21.600 58.300 ;
  END
END NAND3

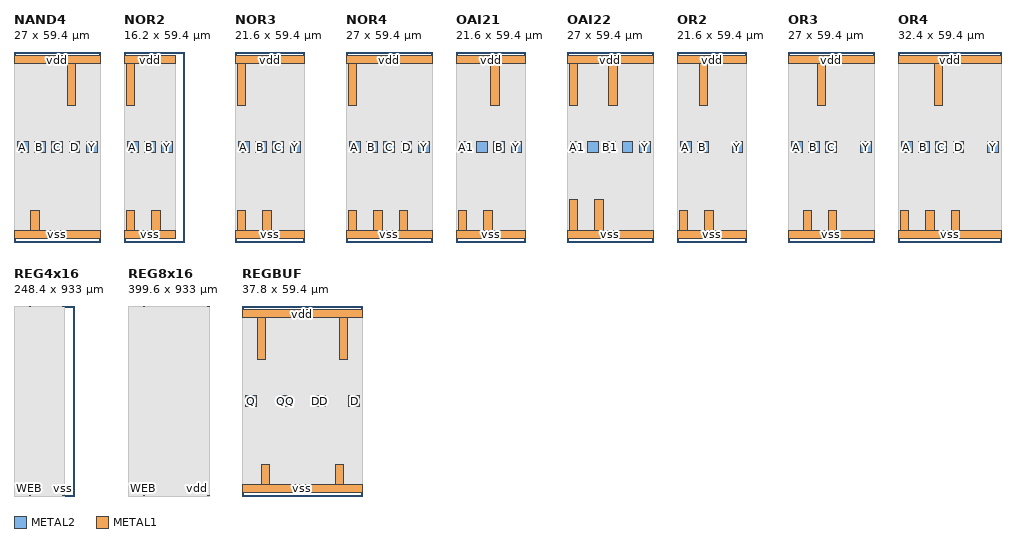
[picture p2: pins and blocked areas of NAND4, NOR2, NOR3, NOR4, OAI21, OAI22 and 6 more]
MACRO NAND4
  CLASS CORE ;
  FOREIGN NAND4 -0.000 -0.000 ;
  ORIGIN 0.000 0.000 ;
  SIZE 27.000 BY 59.400 ;
  SITE TR1UM ;
  SYMMETRY X Y ;
  PIN A
    DIRECTION INPUT ;
    USE SIGNAL ;
    PORT
      LAYER METAL2 ;
        RECT 1.000 28.000 4.400 31.400 ;
    END
  END A
  PIN B
    DIRECTION INPUT ;
    USE SIGNAL ;
    PORT
      LAYER METAL2 ;
        RECT 6.400 28.000 9.800 31.400 ;
    END
  END B
  PIN C
    DIRECTION INPUT ;
    USE SIGNAL ;
    PORT
      LAYER METAL2 ;
        RECT 11.800 28.000 15.200 31.400 ;
    END
  END C
  PIN D
    DIRECTION INPUT ;
    USE SIGNAL ;
    PORT
      LAYER METAL2 ;
        RECT 17.200 28.000 20.600 31.400 ;
    END
  END D
  PIN Y
    DIRECTION OUTPUT ;
    USE SIGNAL ;
    PORT
      LAYER METAL2 ;
        RECT 22.600 28.000 26.000 31.400 ;
    END
  END Y
  PIN vdd
    DIRECTION INOUT ;
    USE POWER ;
    PORT
      LAYER METAL1 ;
        RECT 16.700 42.700 19.300 55.700 ;
        RECT 0.000 55.700 27.000 58.300 ;
    END
  END vdd
  PIN vss
    DIRECTION INOUT ;
    USE GROUND ;
    PORT
      LAYER METAL1 ;
        RECT 0.000 1.100 27.000 3.700 ;
        RECT 5.300 3.700 7.900 9.900 ;
    END
  END vss
  OBS
    LAYER METAL1 ;
      RECT 0.000 1.100 27.000 58.300 ;
  END
END NAND4

MACRO NOR2
  CLASS CORE ;
  FOREIGN NOR2 -0.000 -0.000 ;
  ORIGIN 0.000 0.000 ;
  SIZE 16.200 BY 59.400 ;
  SITE TR1UM ;
  SYMMETRY X Y ;
  PIN A
    DIRECTION INPUT ;
    USE SIGNAL ;
    PORT
      LAYER METAL2 ;
        RECT 1.000 28.000 4.400 31.400 ;
    END
  END A
  PIN B
    DIRECTION INPUT ;
    USE SIGNAL ;
    PORT
      LAYER METAL2 ;
        RECT 6.400 28.000 9.800 31.400 ;
    END
  END B
  PIN Y
    DIRECTION OUTPUT ;
    USE SIGNAL ;
    PORT
      LAYER METAL2 ;
        RECT 11.800 28.000 15.200 31.400 ;
    END
  END Y
  PIN vdd
    DIRECTION INOUT ;
    USE POWER ;
    PORT
      LAYER METAL1 ;
        RECT 0.700 42.700 3.300 55.700 ;
        RECT 0.000 55.700 16.200 58.300 ;
    END
  END vdd
  PIN vss
    DIRECTION INOUT ;
    USE GROUND ;
    PORT
      LAYER METAL1 ;
        RECT 0.000 1.100 16.200 3.700 ;
        RECT 0.700 3.700 3.300 9.900 ;
        RECT 8.700 3.700 11.300 9.900 ;
    END
  END vss
  OBS
    LAYER METAL1 ;
      RECT 0.000 1.100 16.200 58.300 ;
  END
END NOR2

MACRO NOR3
  CLASS CORE ;
  FOREIGN NOR3 -0.000 -0.000 ;
  ORIGIN 0.000 0.000 ;
  SIZE 21.600 BY 59.400 ;
  SITE TR1UM ;
  SYMMETRY X Y ;
  PIN A
    DIRECTION INPUT ;
    USE SIGNAL ;
    PORT
      LAYER METAL2 ;
        RECT 1.000 28.000 4.400 31.400 ;
    END
  END A
  PIN B
    DIRECTION INPUT ;
    USE SIGNAL ;
    PORT
      LAYER METAL2 ;
        RECT 6.400 28.000 9.800 31.400 ;
    END
  END B
  PIN C
    DIRECTION INPUT ;
    USE SIGNAL ;
    PORT
      LAYER METAL2 ;
        RECT 11.800 28.000 15.200 31.400 ;
    END
  END C
  PIN Y
    DIRECTION OUTPUT ;
    USE SIGNAL ;
    PORT
      LAYER METAL2 ;
        RECT 17.200 28.000 20.600 31.400 ;
    END
  END Y
  PIN vdd
    DIRECTION INOUT ;
    USE POWER ;
    PORT
      LAYER METAL1 ;
        RECT 0.700 42.700 3.300 55.700 ;
        RECT 0.000 55.700 21.600 58.300 ;
    END
  END vdd
  PIN vss
    DIRECTION INOUT ;
    USE GROUND ;
    PORT
      LAYER METAL1 ;
        RECT 0.000 1.100 21.600 3.700 ;
        RECT 0.700 3.700 3.300 9.900 ;
        RECT 8.700 3.700 11.300 9.900 ;
    END
  END vss
  OBS
    LAYER METAL1 ;
      RECT 0.000 1.100 21.600 58.300 ;
  END
END NOR3

MACRO NOR4
  CLASS CORE ;
  FOREIGN NOR4 -0.000 -0.000 ;
  ORIGIN 0.000 0.000 ;
  SIZE 27.000 BY 59.400 ;
  SITE TR1UM ;
  SYMMETRY X Y ;
  PIN A
    DIRECTION INPUT ;
    USE SIGNAL ;
    PORT
      LAYER METAL2 ;
        RECT 1.000 28.000 4.400 31.400 ;
    END
  END A
  PIN B
    DIRECTION INPUT ;
    USE SIGNAL ;
    PORT
      LAYER METAL2 ;
        RECT 6.400 28.000 9.800 31.400 ;
    END
  END B
  PIN C
    DIRECTION INPUT ;
    USE SIGNAL ;
    PORT
      LAYER METAL2 ;
        RECT 11.800 28.000 15.200 31.400 ;
    END
  END C
  PIN D
    DIRECTION INPUT ;
    USE SIGNAL ;
    PORT
      LAYER METAL2 ;
        RECT 17.200 28.000 20.600 31.400 ;
    END
  END D
  PIN Y
    DIRECTION OUTPUT ;
    USE SIGNAL ;
    PORT
      LAYER METAL2 ;
        RECT 22.600 28.000 26.000 31.400 ;
    END
  END Y
  PIN vdd
    DIRECTION INOUT ;
    USE POWER ;
    PORT
      LAYER METAL1 ;
        RECT 0.700 42.700 3.300 55.700 ;
        RECT 0.000 55.700 27.000 58.300 ;
    END
  END vdd
  PIN vss
    DIRECTION INOUT ;
    USE GROUND ;
    PORT
      LAYER METAL1 ;
        RECT 0.000 1.100 27.000 3.700 ;
        RECT 0.700 3.700 3.300 9.900 ;
        RECT 8.700 3.700 11.300 9.900 ;
        RECT 16.700 3.700 19.300 9.900 ;
    END
  END vss
  OBS
    LAYER METAL1 ;
      RECT 0.000 1.100 27.000 58.300 ;
  END
END NOR4

MACRO OAI21
  CLASS CORE ;
  FOREIGN OAI21 -0.000 -0.000 ;
  ORIGIN 0.000 0.000 ;
  SIZE 21.600 BY 59.400 ;
  SITE TR1UM ;
  SYMMETRY X Y ;
  PIN A1
    DIRECTION INPUT ;
    USE SIGNAL ;
    PORT
      LAYER METAL2 ;
        RECT 1.000 28.000 4.400 31.400 ;
    END
  END A1
  PIN A2
    DIRECTION INPUT ;
    USE SIGNAL ;
    PORT
      LAYER METAL2 ;
        RECT 6.400 28.000 9.800 31.400 ;
    END
  END A2
  PIN B
    DIRECTION INPUT ;
    USE SIGNAL ;
    PORT
      LAYER METAL2 ;
        RECT 11.800 28.000 15.200 31.400 ;
    END
  END B
  PIN Y
    DIRECTION OUTPUT ;
    USE SIGNAL ;
    PORT
      LAYER METAL2 ;
        RECT 17.200 28.000 20.600 31.400 ;
    END
  END Y
  PIN vdd
    DIRECTION INOUT ;
    USE POWER ;
    PORT
      LAYER METAL1 ;
        RECT 10.900 42.700 13.500 55.700 ;
        RECT 0.000 55.700 21.600 58.300 ;
    END
  END vdd
  PIN vss
    DIRECTION INOUT ;
    USE GROUND ;
    PORT
      LAYER METAL1 ;
        RECT 0.000 1.100 21.600 3.700 ;
        RECT 0.700 3.700 3.300 9.900 ;
        RECT 8.700 3.700 11.300 9.900 ;
    END
  END vss
  OBS
    LAYER METAL1 ;
      RECT 0.000 1.100 21.600 58.300 ;
  END
END OAI21

MACRO OAI22
  CLASS CORE ;
  FOREIGN OAI22 -0.000 -0.000 ;
  ORIGIN 0.000 0.000 ;
  SIZE 27.000 BY 59.400 ;
  SITE TR1UM ;
  SYMMETRY X Y ;
  PIN A1
    DIRECTION INPUT ;
    USE SIGNAL ;
    PORT
      LAYER METAL2 ;
        RECT 1.000 28.000 4.400 31.400 ;
    END
  END A1
  PIN A2
    DIRECTION INPUT ;
    USE SIGNAL ;
    PORT
      LAYER METAL2 ;
        RECT 6.400 28.000 9.800 31.400 ;
    END
  END A2
  PIN B1
    DIRECTION INPUT ;
    USE SIGNAL ;
    PORT
      LAYER METAL2 ;
        RECT 11.800 28.000 15.200 31.400 ;
    END
  END B1
  PIN B2
    DIRECTION INPUT ;
    USE SIGNAL ;
    PORT
      LAYER METAL2 ;
        RECT 17.200 28.000 20.600 31.400 ;
    END
  END B2
  PIN Y
    DIRECTION OUTPUT ;
    USE SIGNAL ;
    PORT
      LAYER METAL2 ;
        RECT 22.600 28.000 26.000 31.400 ;
    END
  END Y
  PIN vdd
    DIRECTION INOUT ;
    USE POWER ;
    PORT
      LAYER METAL1 ;
        RECT 0.700 42.700 3.300 55.700 ;
        RECT 13.100 42.700 15.700 55.700 ;
        RECT 0.000 55.700 27.000 58.300 ;
    END
  END vdd
  PIN vss
    DIRECTION INOUT ;
    USE GROUND ;
    PORT
      LAYER METAL1 ;
        RECT 0.000 1.100 27.000 3.700 ;
        RECT 0.700 3.700 3.300 13.400 ;
        RECT 8.700 3.700 11.300 13.400 ;
    END
  END vss
  OBS
    LAYER METAL1 ;
      RECT 0.000 1.100 27.000 58.300 ;
  END
END OAI22

MACRO OR2
  CLASS CORE ;
  FOREIGN OR2 -0.000 -0.000 ;
  ORIGIN 0.000 0.000 ;
  SIZE 21.600 BY 59.400 ;
  SITE TR1UM ;
  SYMMETRY X Y ;
  PIN A
    DIRECTION INPUT ;
    USE SIGNAL ;
    PORT
      LAYER METAL2 ;
        RECT 1.000 28.000 4.400 31.400 ;
    END
  END A
  PIN B
    DIRECTION INPUT ;
    USE SIGNAL ;
    PORT
      LAYER METAL2 ;
        RECT 6.400 28.000 9.800 31.400 ;
    END
  END B
  PIN Y
    DIRECTION OUTPUT ;
    USE SIGNAL ;
    PORT
      LAYER METAL2 ;
        RECT 17.200 28.000 20.600 31.400 ;
    END
  END Y
  PIN vdd
    DIRECTION INOUT ;
    USE POWER ;
    PORT
      LAYER METAL1 ;
        RECT 6.900 42.700 9.500 55.700 ;
        RECT 0.000 55.700 21.600 58.300 ;
    END
  END vdd
  PIN vss
    DIRECTION INOUT ;
    USE GROUND ;
    PORT
      LAYER METAL1 ;
        RECT 0.000 1.100 21.600 3.700 ;
        RECT 0.700 3.700 3.300 9.900 ;
        RECT 8.700 3.700 11.300 9.900 ;
    END
  END vss
  OBS
    LAYER METAL1 ;
      RECT 0.000 1.100 21.600 58.300 ;
  END
END OR2

MACRO OR3
  CLASS CORE ;
  FOREIGN OR3 -0.000 -0.000 ;
  ORIGIN 0.000 0.000 ;
  SIZE 27.000 BY 59.400 ;
  SITE TR1UM ;
  SYMMETRY X Y ;
  PIN A
    DIRECTION INPUT ;
    USE SIGNAL ;
    PORT
      LAYER METAL2 ;
        RECT 1.000 28.000 4.400 31.400 ;
    END
  END A
  PIN B
    DIRECTION INPUT ;
    USE SIGNAL ;
    PORT
      LAYER METAL2 ;
        RECT 6.400 28.000 9.800 31.400 ;
    END
  END B
  PIN C
    DIRECTION INPUT ;
    USE SIGNAL ;
    PORT
      LAYER METAL2 ;
        RECT 11.800 28.000 15.200 31.400 ;
    END
  END C
  PIN Y
    DIRECTION OUTPUT ;
    USE SIGNAL ;
    PORT
      LAYER METAL2 ;
        RECT 22.600 28.000 26.000 31.400 ;
    END
  END Y
  PIN vdd
    DIRECTION INOUT ;
    USE POWER ;
    PORT
      LAYER METAL1 ;
        RECT 9.100 42.700 11.700 55.700 ;
        RECT 0.000 55.700 27.000 58.300 ;
    END
  END vdd
  PIN vss
    DIRECTION INOUT ;
    USE GROUND ;
    PORT
      LAYER METAL1 ;
        RECT 0.000 1.100 27.000 3.700 ;
        RECT 4.700 3.700 7.300 9.900 ;
        RECT 12.700 3.700 15.300 9.900 ;
    END
  END vss
  OBS
    LAYER METAL1 ;
      RECT 0.000 1.100 27.000 58.300 ;
  END
END OR3

MACRO OR4
  CLASS CORE ;
  FOREIGN OR4 -0.000 -0.000 ;
  ORIGIN 0.000 0.000 ;
  SIZE 32.400 BY 59.400 ;
  SITE TR1UM ;
  SYMMETRY X Y ;
  PIN A
    DIRECTION INPUT ;
    USE SIGNAL ;
    PORT
      LAYER METAL2 ;
        RECT 1.000 28.000 4.400 31.400 ;
    END
  END A
  PIN B
    DIRECTION INPUT ;
    USE SIGNAL ;
    PORT
      LAYER METAL2 ;
        RECT 6.400 28.000 9.800 31.400 ;
    END
  END B
  PIN C
    DIRECTION INPUT ;
    USE SIGNAL ;
    PORT
      LAYER METAL2 ;
        RECT 11.800 28.000 15.200 31.400 ;
    END
  END C
  PIN D
    DIRECTION INPUT ;
    USE SIGNAL ;
    PORT
      LAYER METAL2 ;
        RECT 17.200 28.000 20.600 31.400 ;
    END
  END D
  PIN Y
    DIRECTION OUTPUT ;
    USE SIGNAL ;
    PORT
      LAYER METAL2 ;
        RECT 28.000 28.000 31.400 31.400 ;
    END
  END Y
  PIN vdd
    DIRECTION INOUT ;
    USE POWER ;
    PORT
      LAYER METAL1 ;
        RECT 11.300 42.700 13.900 55.700 ;
        RECT 0.000 55.700 32.400 58.300 ;
    END
  END vdd
  PIN vss
    DIRECTION INOUT ;
    USE GROUND ;
    PORT
      LAYER METAL1 ;
        RECT 0.000 1.100 32.400 3.700 ;
        RECT 0.700 3.700 3.300 9.900 ;
        RECT 8.700 3.700 11.300 9.900 ;
        RECT 16.700 3.700 19.300 9.900 ;
    END
  END vss
  OBS
    LAYER METAL1 ;
      RECT 0.000 1.100 32.400 58.300 ;
  END
END OR4

MACRO REG4x16
  CLASS BLOCK ;
  FOREIGN REG4x16 -0.000 -0.000 ;
  ORIGIN 0.000 0.000 ;
  SIZE 248.400 BY 933.000 ;
  SYMMETRY X Y ;
  PIN WEB
    DIRECTION INOUT ;
    USE SIGNAL ;
    PORT
      LAYER METAL2 ;
        RECT 6.400 1.100 9.800 4.500 ;
    END
  END WEB
  PIN vdd
    DIRECTION INOUT ;
    USE POWER ;
    PORT
      LAYER METAL1 ;
        RECT 76.600 1.100 80.000 4.500 ;
        RECT 244.000 1.100 247.400 4.500 ;
        RECT 76.600 928.500 80.000 931.900 ;
        RECT 244.000 928.500 247.400 931.900 ;
    END
  END vdd
  PIN vss
    DIRECTION INOUT ;
    USE GROUND ;
    PORT
      LAYER METAL1 ;
        RECT 1.000 1.100 4.400 4.500 ;
        RECT 238.600 1.100 242.000 4.500 ;
        RECT 1.000 928.500 4.400 931.900 ;
        RECT 238.600 928.500 242.000 931.900 ;
    END
  END vss
  OBS
    LAYER METAL1 ;
      RECT 0.000 0.000 248.400 933.000 ;
    LAYER METAL2 ;
      RECT 0.000 0.000 248.400 933.000 ;
  END
END REG4x16

MACRO REG8x16
  CLASS BLOCK ;
  FOREIGN REG8x16 -0.000 -0.000 ;
  ORIGIN 0.000 0.000 ;
  SIZE 399.600 BY 933.000 ;
  SYMMETRY X Y ;
  PIN WEB
    DIRECTION INPUT ;
    USE SIGNAL ;
    PORT
      LAYER METAL2 ;
        RECT 6.400 1.100 9.800 4.500 ;
    END
  END WEB
  PIN vdd
    DIRECTION INOUT ;
    USE POWER ;
    PORT
      LAYER METAL1 ;
        RECT 76.600 1.100 80.000 4.500 ;
        RECT 395.200 1.100 398.600 4.500 ;
        RECT 76.600 928.500 80.000 931.900 ;
        RECT 395.200 928.500 398.600 931.900 ;
    END
  END vdd
  PIN vss
    DIRECTION INOUT ;
    USE GROUND ;
    PORT
      LAYER METAL1 ;
        RECT 1.000 1.100 4.400 4.500 ;
        RECT 389.800 1.100 393.200 4.500 ;
        RECT 1.000 928.500 4.400 931.900 ;
        RECT 389.800 928.500 393.200 931.900 ;
    END
  END vss
  OBS
    LAYER METAL1 ;
      RECT 0.000 0.000 399.600 933.000 ;
    LAYER METAL2 ;
      RECT 0.000 0.000 399.600 933.000 ;
  END
END REG8x16

MACRO REGBUF
  CLASS BLOCK ;
  FOREIGN REGBUF -0.000 -0.000 ;
  ORIGIN 0.000 0.000 ;
  SIZE 37.800 BY 59.400 ;
  SYMMETRY X Y ;
  PIN D
    DIRECTION INOUT ;
    USE SIGNAL ;
    PORT
      LAYER METAL2 ;
        RECT 33.400 28.000 36.800 31.400 ;
    END
  END D
  PIN DD
    DIRECTION INOUT ;
    USE SIGNAL ;
    PORT
      LAYER METAL2 ;
        RECT 22.600 28.000 26.000 31.400 ;
    END
  END DD
  PIN Q
    DIRECTION INOUT ;
    USE SIGNAL ;
    PORT
      LAYER METAL2 ;
        RECT 1.000 28.000 4.400 31.400 ;
    END
  END Q
  PIN QQ
    DIRECTION INOUT ;
    USE SIGNAL ;
    PORT
      LAYER METAL2 ;
        RECT 11.800 28.000 15.200 31.400 ;
    END
  END QQ
  PIN vdd
    DIRECTION INOUT ;
    USE POWER ;
    PORT
      LAYER METAL1 ;
        RECT 4.700 42.700 7.300 55.700 ;
        RECT 30.500 42.700 33.100 55.700 ;
        RECT 0.000 55.700 37.800 58.300 ;
    END
  END vdd
  PIN vss
    DIRECTION INOUT ;
    USE GROUND ;
    PORT
      LAYER METAL1 ;
        RECT 0.000 1.100 37.800 3.700 ;
        RECT 6.100 3.700 8.700 9.900 ;
        RECT 29.100 3.700 31.700 9.900 ;
    END
  END vss
  OBS
    LAYER METAL1 ;
      RECT 0.000 1.100 37.800 58.300 ;
  END
END REGBUF

MACRO REGBUF4
  CLASS BLOCK ;
  FOREIGN REGBUF4 10.800 -0.000 ;
  ORIGIN 0.000 0.000 ;
  SIZE 162.000 BY 59.400 ;
  SYMMETRY X Y ;
  # ★ ピン未定義: GDS のトップにラベル/(49,1) 形状を入れて再生成すること

  OBS
    LAYER METAL1 ;
      RECT 0.000 1.100 162.000 58.300 ;
    LAYER METAL2 ;
      RECT 0.000 0.000 162.000 59.400 ;
  END
END REGBUF4

MACRO REGBUF8
  CLASS BLOCK ;
  FOREIGN REGBUF8 10.800 -0.000 ;
  ORIGIN 0.000 0.000 ;
  SIZE 313.200 BY 59.400 ;
  SYMMETRY X Y ;
  # ★ ピン未定義: GDS のトップにラベル/(49,1) 形状を入れて再生成すること

  OBS
    LAYER METAL1 ;
      RECT 0.000 1.100 313.200 58.300 ;
    LAYER METAL2 ;
      RECT 0.000 0.000 313.200 59.400 ;
  END
END REGBUF8

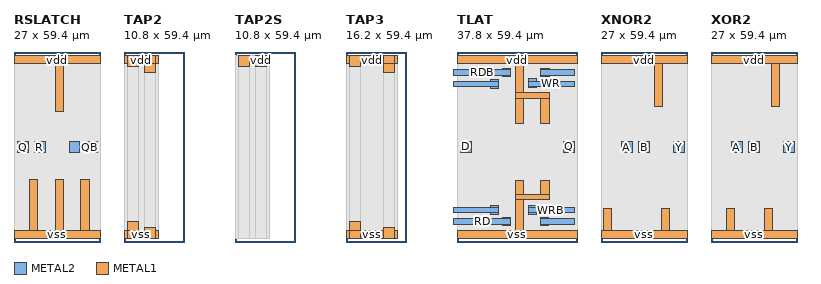
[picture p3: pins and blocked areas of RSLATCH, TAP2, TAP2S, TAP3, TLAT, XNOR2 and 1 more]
MACRO RSLATCH
  CLASS CORE ;
  FOREIGN RSLATCH -0.000 -0.000 ;
  ORIGIN 0.000 0.000 ;
  SIZE 27.000 BY 59.400 ;
  SITE TR1UM ;
  SYMMETRY X Y ;
  PIN Q
    DIRECTION OUTPUT ;
    USE SIGNAL ;
    PORT
      LAYER METAL2 ;
        RECT 1.000 28.000 4.400 31.400 ;
    END
  END Q
  PIN QB
    DIRECTION OUTPUT ;
    USE SIGNAL ;
    PORT
      LAYER METAL2 ;
        RECT 22.600 28.000 26.000 31.400 ;
    END
  END QB
  PIN R
    DIRECTION INPUT ;
    USE SIGNAL ;
    PORT
      LAYER METAL2 ;
        RECT 6.400 28.000 9.800 31.400 ;
    END
  END R
  PIN S
    DIRECTION INPUT ;
    USE SIGNAL ;
    PORT
      LAYER METAL2 ;
        RECT 17.200 28.000 20.600 31.400 ;
    END
  END S
  PIN vdd
    DIRECTION INOUT ;
    USE POWER ;
    PORT
      LAYER METAL1 ;
        RECT 12.900 40.700 15.500 55.700 ;
        RECT 0.000 55.700 27.000 58.300 ;
    END
  END vdd
  PIN vss
    DIRECTION INOUT ;
    USE GROUND ;
    PORT
      LAYER METAL1 ;
        RECT 0.000 1.100 27.000 3.700 ;
        RECT 4.900 3.700 7.500 19.600 ;
        RECT 12.900 3.700 15.500 19.600 ;
        RECT 20.900 3.700 23.500 19.600 ;
    END
  END vss
  OBS
    LAYER METAL1 ;
      RECT 0.000 1.100 27.000 58.300 ;
  END
END RSLATCH

MACRO TAP2
  CLASS CORE WELLTAP ;
  FOREIGN TAP2 -0.000 -0.000 ;
  ORIGIN 0.000 0.000 ;
  SIZE 10.800 BY 59.400 ;
  SITE TR1UM ;
  SYMMETRY X Y ;
  PIN vdd
    DIRECTION INOUT ;
    USE POWER ;
    PORT
      LAYER METAL1 ;
        RECT 6.400 1.100 9.800 4.500 ;
        RECT 6.400 54.900 9.800 58.300 ;
        RECT 6.400 53.100 9.800 55.700 ;
        RECT 0.000 55.700 10.800 58.300 ;
    END
  END vdd
  PIN vss
    DIRECTION INOUT ;
    USE GROUND ;
    PORT
      LAYER METAL1 ;
        RECT 1.000 1.100 4.400 4.500 ;
        RECT 1.000 54.900 4.400 58.300 ;
        RECT 0.000 1.100 10.800 3.700 ;
        RECT 1.000 3.700 4.400 6.300 ;
    END
  END vss
  OBS
    LAYER METAL1 ;
      RECT 0.000 1.100 10.800 58.300 ;
    LAYER METAL2 ;
      RECT 6.400 4.500 9.800 53.100 ;
      RECT 1.000 6.300 4.400 54.900 ;
  END
END TAP2

MACRO TAP2S
  CLASS BLOCK ;
  FOREIGN TAP2S -0.000 -0.000 ;
  ORIGIN 0.000 0.000 ;
  SIZE 10.800 BY 59.400 ;
  SYMMETRY X Y ;
  PIN vdd
    DIRECTION INOUT ;
    USE POWER ;
    PORT
      LAYER METAL1 ;
        RECT 6.400 54.900 9.800 58.300 ;
    END
  END vdd
  PIN vss
    DIRECTION INOUT ;
    USE GROUND ;
    PORT
      LAYER METAL1 ;
        RECT 1.000 54.900 4.400 58.300 ;
    END
  END vss
  OBS
    LAYER METAL1 ;
      RECT 0.000 1.100 10.800 58.300 ;
    LAYER METAL2 ;
      RECT 1.000 1.100 4.400 54.900 ;
      RECT 6.400 1.100 9.800 54.900 ;
  END
END TAP2S

MACRO TAP3
  CLASS CORE WELLTAP ;
  FOREIGN TAP3 -0.000 -0.000 ;
  ORIGIN 0.000 0.000 ;
  SIZE 16.200 BY 59.400 ;
  SITE TR1UM ;
  SYMMETRY X Y ;
  PIN vdd
    DIRECTION INOUT ;
    USE POWER ;
    PORT
      LAYER METAL1 ;
        RECT 11.800 1.100 15.200 4.500 ;
        RECT 11.800 54.900 15.200 58.300 ;
        RECT 11.800 53.100 15.200 55.700 ;
        RECT 0.000 55.700 16.200 58.300 ;
    END
  END vdd
  PIN vss
    DIRECTION INOUT ;
    USE GROUND ;
    PORT
      LAYER METAL1 ;
        RECT 1.000 1.100 4.400 4.500 ;
        RECT 1.000 54.900 4.400 58.300 ;
        RECT 0.000 1.100 16.200 3.700 ;
        RECT 1.000 3.700 4.400 6.300 ;
    END
  END vss
  OBS
    LAYER METAL1 ;
      RECT 0.000 1.100 16.200 58.300 ;
    LAYER METAL2 ;
      RECT 11.800 4.500 15.200 53.100 ;
      RECT 1.000 6.300 4.400 54.900 ;
  END
END TAP3

MACRO TLAT
  CLASS BLOCK ;
  FOREIGN TLAT -0.000 -0.000 ;
  ORIGIN 0.000 0.000 ;
  SIZE 37.800 BY 59.400 ;
  SYMMETRY X Y ;
  PIN D
    DIRECTION INOUT ;
    USE SIGNAL ;
    PORT
      LAYER METAL2 ;
        RECT 1.000 28.100 4.400 31.500 ;
    END
  END D
  PIN Q
    DIRECTION INOUT ;
    USE SIGNAL ;
    PORT
      LAYER METAL2 ;
        RECT 33.400 28.100 36.800 31.500 ;
    END
  END Q
  PIN RD
    DIRECTION INOUT ;
    USE SIGNAL ;
    PORT
      LAYER METAL2 ;
        RECT 14.200 5.100 16.800 5.500 ;
        RECT 26.000 5.100 28.600 5.500 ;
        RECT -1.000 5.500 16.800 7.300 ;
        RECT 26.000 5.500 36.800 7.300 ;
        RECT 14.200 7.300 16.800 7.700 ;
        RECT 26.000 7.300 28.600 7.700 ;
    END
  END RD
  PIN RDB
    DIRECTION INOUT ;
    USE SIGNAL ;
    PORT
      LAYER METAL2 ;
        RECT 14.200 51.700 16.800 52.100 ;
        RECT 26.200 51.700 28.800 52.100 ;
        RECT -1.000 52.100 16.800 53.900 ;
        RECT 26.200 52.100 36.800 53.900 ;
        RECT 14.200 53.900 16.800 54.300 ;
        RECT 26.200 53.900 28.800 54.300 ;
    END
  END RDB
  PIN WR
    DIRECTION INOUT ;
    USE SIGNAL ;
    PORT
      LAYER METAL2 ;
        RECT 10.400 48.100 13.000 48.500 ;
        RECT 22.200 48.400 24.800 48.500 ;
        RECT -1.000 48.500 13.000 50.300 ;
        RECT 22.200 48.500 36.800 50.300 ;
        RECT 10.400 50.300 13.000 50.700 ;
        RECT 22.200 50.300 24.800 51.000 ;
    END
  END WR
  PIN WRB
    DIRECTION INOUT ;
    USE SIGNAL ;
    PORT
      LAYER METAL2 ;
        RECT 10.400 8.700 13.000 9.100 ;
        RECT 22.200 8.700 24.800 9.100 ;
        RECT -1.000 9.100 13.000 10.900 ;
        RECT 22.200 9.100 36.800 10.900 ;
        RECT 10.400 10.900 13.000 11.300 ;
        RECT 22.200 10.900 24.800 11.300 ;
    END
  END WRB
  PIN vdd
    DIRECTION INOUT ;
    USE POWER ;
    PORT
      LAYER METAL1 ;
        RECT 18.200 36.900 20.800 44.900 ;
        RECT 26.200 36.900 28.800 44.900 ;
        RECT 18.200 44.900 28.800 46.700 ;
        RECT 18.200 46.700 20.800 55.700 ;
        RECT 0.000 55.700 37.800 58.300 ;
    END
  END vdd
  PIN vss
    DIRECTION INOUT ;
    USE GROUND ;
    PORT
      LAYER METAL1 ;
        RECT 0.000 1.100 37.800 3.700 ;
        RECT 18.200 3.700 20.800 13.200 ;
        RECT 18.200 13.200 28.800 15.000 ;
        RECT 18.200 15.000 20.800 19.200 ;
        RECT 26.200 15.000 28.800 19.200 ;
    END
  END vss
  OBS
    LAYER METAL1 ;
      RECT 0.000 1.100 37.800 58.300 ;
  END
END TLAT

MACRO TLAT128
  CLASS BLOCK ;
  FOREIGN TLAT128 -0.000 -0.000 ;
  ORIGIN 0.000 0.000 ;
  SIZE 313.200 BY 878.400 ;
  SYMMETRY X Y ;
  # ★ ピン未定義: GDS のトップにラベル/(49,1) 形状を入れて再生成すること

  OBS
    LAYER METAL1 ;
      RECT 0.000 0.000 313.200 878.400 ;
    LAYER METAL2 ;
      RECT 0.000 0.000 313.200 878.400 ;
  END
END TLAT128

MACRO TLAT4
  CLASS BLOCK ;
  FOREIGN TLAT4 -0.000 -0.000 ;
  ORIGIN 0.000 0.000 ;
  SIZE 162.000 BY 59.400 ;
  SYMMETRY X Y ;
  # ★ ピン未定義: GDS のトップにラベル/(49,1) 形状を入れて再生成すること

  OBS
    LAYER METAL1 ;
      RECT 0.000 1.100 162.000 58.300 ;
    LAYER METAL2 ;
      RECT 0.000 0.000 162.000 59.400 ;
  END
END TLAT4

MACRO TLAT4B
  CLASS BLOCK ;
  FOREIGN TLAT4B -0.000 -0.000 ;
  ORIGIN 0.000 0.000 ;
  SIZE 162.000 BY 114.000 ;
  SYMMETRY X Y ;
  # ★ ピン未定義: GDS のトップにラベル/(49,1) 形状を入れて再生成すること

  OBS
    LAYER METAL1 ;
      RECT 0.000 0.000 162.000 114.000 ;
    LAYER METAL2 ;
      RECT 0.000 0.000 162.000 114.000 ;
  END
END TLAT4B

MACRO TLAT64
  CLASS BLOCK ;
  FOREIGN TLAT64 -0.000 -0.000 ;
  ORIGIN 0.000 0.000 ;
  SIZE 162.000 BY 878.400 ;
  SYMMETRY X Y ;
  # ★ ピン未定義: GDS のトップにラベル/(49,1) 形状を入れて再生成すること

  OBS
    LAYER METAL1 ;
      RECT 0.000 0.000 162.000 878.400 ;
    LAYER METAL2 ;
      RECT 0.000 0.000 162.000 878.400 ;
  END
END TLAT64

MACRO TLAT8
  CLASS BLOCK ;
  FOREIGN TLAT8 -0.000 -0.000 ;
  ORIGIN 0.000 0.000 ;
  SIZE 313.200 BY 59.400 ;
  SYMMETRY X Y ;
  # ★ ピン未定義: GDS のトップにラベル/(49,1) 形状を入れて再生成すること

  OBS
    LAYER METAL1 ;
      RECT 0.000 1.100 313.200 58.300 ;
    LAYER METAL2 ;
      RECT 0.000 0.000 313.200 59.400 ;
  END
END TLAT8

MACRO TLAT8B
  CLASS BLOCK ;
  FOREIGN TLAT8B -0.000 -0.000 ;
  ORIGIN 0.000 0.000 ;
  SIZE 313.200 BY 114.000 ;
  SYMMETRY X Y ;
  # ★ ピン未定義: GDS のトップにラベル/(49,1) 形状を入れて再生成すること

  OBS
    LAYER METAL1 ;
      RECT 0.000 0.000 313.200 114.000 ;
    LAYER METAL2 ;
      RECT 0.000 0.000 313.200 114.000 ;
  END
END TLAT8B

MACRO XNOR2
  CLASS CORE ;
  FOREIGN XNOR2 -0.000 -0.000 ;
  ORIGIN 0.000 0.000 ;
  SIZE 27.000 BY 59.400 ;
  SITE TR1UM ;
  SYMMETRY X Y ;
  PIN A
    DIRECTION INPUT ;
    USE SIGNAL ;
    PORT
      LAYER METAL2 ;
        RECT 6.400 27.900 9.800 31.300 ;
    END
  END A
  PIN B
    DIRECTION INPUT ;
    USE SIGNAL ;
    PORT
      LAYER METAL2 ;
        RECT 11.800 27.900 15.200 31.300 ;
    END
  END B
  PIN Y
    DIRECTION OUTPUT ;
    USE SIGNAL ;
    PORT
      LAYER METAL2 ;
        RECT 22.600 27.900 26.000 31.300 ;
    END
  END Y
  PIN vdd
    DIRECTION INOUT ;
    USE POWER ;
    PORT
      LAYER METAL1 ;
        RECT 16.700 42.500 19.300 55.700 ;
        RECT 0.000 55.700 27.000 58.300 ;
    END
  END vdd
  PIN vss
    DIRECTION INOUT ;
    USE GROUND ;
    PORT
      LAYER METAL1 ;
        RECT 0.000 1.100 27.000 3.700 ;
        RECT 0.700 3.700 3.300 10.500 ;
        RECT 18.900 3.700 21.500 10.500 ;
    END
  END vss
  OBS
    LAYER METAL1 ;
      RECT 0.000 1.100 27.000 58.300 ;
  END
END XNOR2

MACRO XOR2
  CLASS CORE ;
  FOREIGN XOR2 -0.000 -0.000 ;
  ORIGIN 0.000 0.000 ;
  SIZE 27.000 BY 59.400 ;
  SITE TR1UM ;
  SYMMETRY X Y ;
  PIN A
    DIRECTION INPUT ;
    USE SIGNAL ;
    PORT
      LAYER METAL2 ;
        RECT 6.400 27.900 9.800 31.300 ;
    END
  END A
  PIN B
    DIRECTION INPUT ;
    USE SIGNAL ;
    PORT
      LAYER METAL2 ;
        RECT 11.800 27.900 15.200 31.300 ;
    END
  END B
  PIN Y
    DIRECTION OUTPUT ;
    USE SIGNAL ;
    PORT
      LAYER METAL2 ;
        RECT 22.600 27.900 26.000 31.300 ;
    END
  END Y
  PIN vdd
    DIRECTION INOUT ;
    USE POWER ;
    PORT
      LAYER METAL1 ;
        RECT 18.900 42.500 21.500 55.700 ;
        RECT 0.000 55.700 27.000 58.300 ;
    END
  END vdd
  PIN vss
    DIRECTION INOUT ;
    USE GROUND ;
    PORT
      LAYER METAL1 ;
        RECT 0.000 1.100 27.000 3.700 ;
        RECT 4.700 3.700 7.300 10.500 ;
        RECT 16.700 3.700 19.300 10.500 ;
    END
  END vss
  OBS
    LAYER METAL1 ;
      RECT 0.000 1.100 27.000 58.300 ;
  END
END XOR2

END LIBRARY
